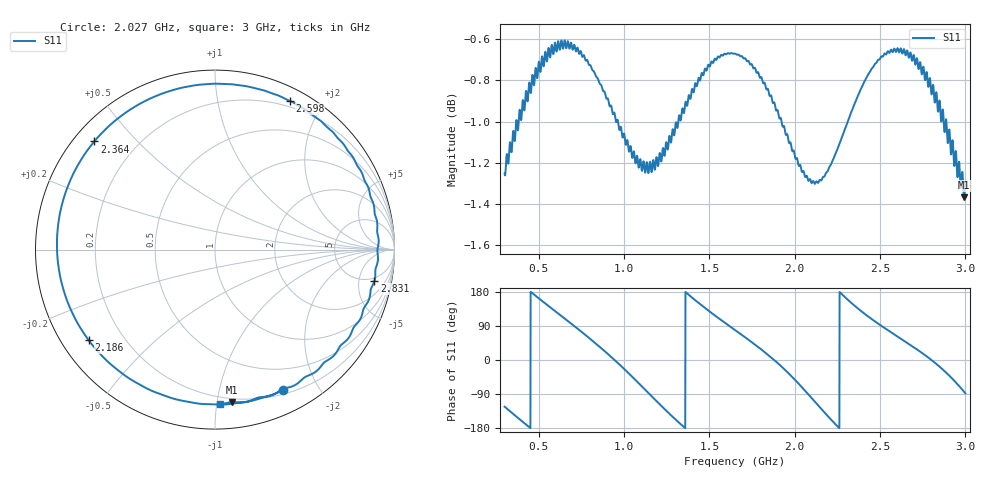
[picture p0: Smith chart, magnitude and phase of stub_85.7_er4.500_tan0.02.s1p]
! Chirptenna · simulación 3D de un stub abierto
# HZ S RI R 50
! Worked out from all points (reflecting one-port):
!   2001 points, 300 MHz to 3 GHz, reference 50 ohm
!   lowest |S11| = -1.4 dB at 2.992 GHz (marker M1), VSWR 12.72, Z = 8.74 - j54.9 ohm
!   phase of S11 starts at -123 deg and turns -1045 deg over the sweep
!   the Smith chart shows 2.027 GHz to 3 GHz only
!   S11 on the Smith chart (normalised r, x): 2.027 GHz: 0.24, -1.57; 2.186 GHz: 0.08, -0.32; 2.364 GHz: 0.06, +0.38; 2.598 GHz: 0.14, +1.61; 2.831 GHz: 4.18, -8.12; 3 GHz: 0.15, -1.02
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3e8  -0.4746 -0.7241
4.701e8  -0.9041 0.1048
6.375e8  -0.3827 0.8482
7.914e8  0.4678 0.7929
8.913e8  0.8421 0.3301
9.75e8  0.8657 -0.1949
1.06815e9  0.5199 -0.6986
1.14375e9  0.038 -0.8653
1.218e9  -0.4485 -0.7473
1.3125e9  -0.8423 -0.2816
1.40295e9  -0.8666 0.2673
1.50015e9  -0.5687 0.7222
1.65e9  0.1749 0.9092
1.839e9  0.8751 0.2412
1.9875e9  0.6129 -0.6267
2.02665e9  0.3799 -0.7821
2.1036e9  -0.1875 -0.8409
2.18595e9  -0.7036 -0.5055
2.25345e9  -0.8766 -0.0567
2.325e9  -0.799 0.4024
2.36415e9  -0.6729 0.6023
2.47755e9  -0.1511 0.9085
2.5977e9  0.4167 0.8289
2.6625e9  0.6653 0.6446
2.83125e9  0.8883 -0.175
2.91225e9  0.6248 -0.6177
2.9919e9  0.0921 -0.8493
3e9  0.0291 -0.8615
